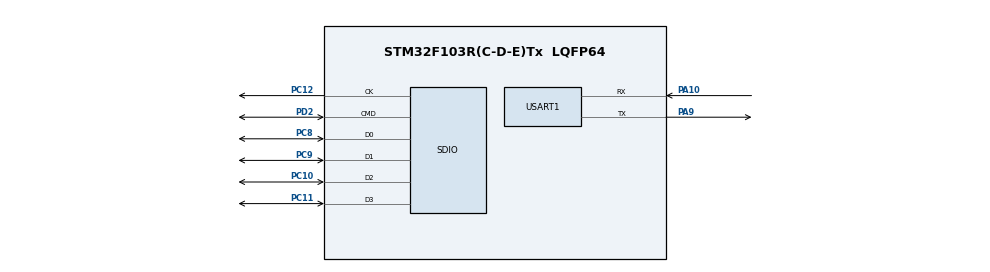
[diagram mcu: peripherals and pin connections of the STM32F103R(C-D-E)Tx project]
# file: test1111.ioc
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Dma.Request0=USART1_RX
Dma.Request1=USART1_TX
Dma.USART1_RX.0.Direction=DMA_PERIPH_TO_MEMORY
Dma.USART1_RX.0.Instance=DMA1_Channel5
Dma.USART1_RX.0.MemDataAlignment=DMA_MDATAALIGN_BYTE
Dma.USART1_RX.0.MemInc=DMA_MINC_ENABLE
Dma.USART1_RX.0.Mode=DMA_NORMAL
Dma.USART1_RX.0.PeriphDataAlignment=DMA_PDATAALIGN_BYTE
Dma.USART1_RX.0.PeriphInc=DMA_PINC_DISABLE
Dma.USART1_RX.0.Priority=DMA_PRIORITY_LOW
Dma.USART1_TX.1.Direction=DMA_MEMORY_TO_PERIPH
Dma.USART1_TX.1.Instance=DMA1_Channel4
Dma.USART1_TX.1.MemDataAlignment=DMA_MDATAALIGN_HALFWORD
Dma.USART1_TX.1.MemInc=DMA_MINC_ENABLE
Dma.USART1_TX.1.Mode=DMA_NORMAL
Dma.USART1_TX.1.PeriphDataAlignment=DMA_PDATAALIGN_HALFWORD
Dma.USART1_TX.1.PeriphInc=DMA_PINC_DISABLE
Dma.USART1_TX.1.Priority=DMA_PRIORITY_LOW
FREERTOS.Tasks01=defaultTask,0,128,StartDefaultTask,Default,NULL
Mcu.Family=STM32F1
Mcu.Name=STM32F103R(C-D-E)Tx
Mcu.Package=LQFP64
NVIC.DMA1_Channel4_IRQn=true\:5\:0\:false\:false\:true\:true
NVIC.DMA1_Channel5_IRQn=true\:5\:0\:false\:false\:true\:true
NVIC.PriorityGroup=NVIC_PRIORITYGROUP_4
PA10.Mode=Asynchronous
PA10.Signal=USART1_RX
PA9.Mode=Asynchronous
PA9.Signal=USART1_TX
PC10.Mode=SD_4_bits_Wide_bus
PC10.Signal=SDIO_D2
PC11.Mode=SD_4_bits_Wide_bus
PC11.Signal=SDIO_D3
PC12.Mode=SD_4_bits_Wide_bus
PC12.Signal=SDIO_CK
PC8.Mode=SD_4_bits_Wide_bus
PC8.Signal=SDIO_D0
PC9.Mode=SD_4_bits_Wide_bus
PC9.Signal=SDIO_D1
PD0-OSC_IN.Mode=HSE-External-Oscillator
PD0-OSC_IN.Signal=RCC_OSC_IN
PD1-OSC_OUT.Mode=HSE-External-Oscillator
PD1-OSC_OUT.Signal=RCC_OSC_OUT
PD2.Mode=SD_4_bits_Wide_bus
PD2.Signal=SDIO_CMD
ProjectManager.HeapSize=0x200
ProjectManager.StackSize=0x400
ProjectManager.TargetToolchain=MDK-ARM V5
RCC.AHBFreq_Value=72000000
RCC.APB1CLKDivider=RCC_HCLK_DIV2
RCC.APB1Freq_Value=36000000
RCC.APB1TimFreq_Value=72000000
RCC.APB2Freq_Value=72000000
RCC.APB2TimFreq_Value=72000000
RCC.HCLKFreq_Value=72000000
RCC.PLLMUL=RCC_PLL_MUL9
RCC.PLLSourceVirtual=RCC_PLLSOURCE_HSE
RCC.SYSCLKFreq_VALUE=72000000
RCC.SYSCLKSource=RCC_SYSCLKSOURCE_PLLCLK
RCC.USBFreq_Value=72000000
USART1.VirtualMode=VM_ASYNC
VP_FREERTOS_VS_ENABLE.Mode=Enabled
VP_SYS_VS_ND.Mode=No_Debug
VP_TIM3_VS_ClockSourceINT.Mode=Internal
board=test1111

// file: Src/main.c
/**
  ******************************************************************************
  * File Name          : main.c
  * Description        : Main program body
  ******************************************************************************
  * This notice applies to any and all portions of this file
  * that are not between comment pairs USER CODE BEGIN and
  * USER CODE END. Other portions of this file, whether
  * inserted by the user or by software development tools
  * are owned by their respective copyright owners.
  *
  * Copyright (c) 2017 STMicroelectronics International N.V.
  * All rights reserved.
  *
  * Redistribution and use in source and binary forms, with or without
  * modification, are permitted, provided that the following conditions are met:
  *
  * 1. Redistribution of source code must retain the above copyright notice,
  *    this list of conditions and the following disclaimer.
  * 2. Redistributions in binary form must reproduce the above copyright notice,
  *    this list of conditions and the following disclaimer in the documentation
  *    and/or other materials provided with the distribution.
  * 3. Neither the name of STMicroelectronics nor the names of other
  *    contributors to this software may be used to endorse or promote products
  *    derived from this software without specific written permission.
  * 4. This software, including modifications and/or derivative works of this
  *    software, must execute solely and exclusively on microcontroller or
  *    microprocessor devices manufactured by or for STMicroelectronics.
  * 5. Redistribution and use of this software other than as permitted under
  *    this license is void and will automatically terminate your rights under
  *    this license.
  *
  * THIS SOFTWARE IS PROVIDED BY STMICROELECTRONICS AND CONTRIBUTORS "AS IS"
  * AND ANY EXPRESS, IMPLIED OR STATUTORY WARRANTIES, INCLUDING, BUT NOT
  * LIMITED TO, THE IMPLIED WARRANTIES OF MERCHANTABILITY, FITNESS FOR A
  * PARTICULAR PURPOSE AND NON-INFRINGEMENT OF THIRD PARTY INTELLECTUAL PROPERTY
  * RIGHTS ARE DISCLAIMED TO THE FULLEST EXTENT PERMITTED BY LAW. IN NO EVENT
  * SHALL STMICROELECTRONICS OR CONTRIBUTORS BE LIABLE FOR ANY DIRECT, INDIRECT,
  * INCIDENTAL, SPECIAL, EXEMPLARY, OR CONSEQUENTIAL DAMAGES (INCLUDING, BUT NOT
  * LIMITED TO, PROCUREMENT OF SUBSTITUTE GOODS OR SERVICES; LOSS OF USE, DATA,
  * OR PROFITS; OR BUSINESS INTERRUPTION) HOWEVER CAUSED AND ON ANY THEORY OF
  * LIABILITY, WHETHER IN CONTRACT, STRICT LIABILITY, OR TORT (INCLUDING
  * NEGLIGENCE OR OTHERWISE) ARISING IN ANY WAY OUT OF THE USE OF THIS SOFTWARE,
  * EVEN IF ADVISED OF THE POSSIBILITY OF SUCH DAMAGE.
  *
  ******************************************************************************
  */
#include "main.h"
#include "stm32f1xx_hal.h"
#include "cmsis_os.h"
#include "dma.h"
#include "sdio.h"
#include "tim.h"
#include "usart.h"
#include "gpio.h"

/* USER CODE BEGIN PV */
/* Private variables ---------------------------------------------------------*/

/* USER CODE END PV */

void SystemClock_Config(void);
void MX_FREERTOS_Init(void);

/* USER CODE BEGIN PFP */
/* Private function prototypes -----------------------------------------------*/

/* USER CODE END PFP */

int main(void)
{

  /* MCU Configuration----------------------------------------------------------*/

  /* Reset of all peripherals, Initializes the Flash interface and the Systick. */
  HAL_Init();

  /* Configure the system clock */
  SystemClock_Config();

  /* Initialize all configured peripherals */
  MX_GPIO_Init();
  MX_DMA_Init();
  MX_USART1_UART_Init();
  MX_SDIO_SD_Init();
  MX_TIM3_Init();

  /* Call init function for freertos objects (in freertos.c) */
  MX_FREERTOS_Init();

  /* Start scheduler */
  osKernelStart();

  /* We should never get here as control is now taken by the scheduler */

  /* Infinite loop */
  while (1)
  {

  }

}

/** System Clock Configuration
*/
void SystemClock_Config(void)
{

  RCC_OscInitTypeDef RCC_OscInitStruct;
  RCC_ClkInitTypeDef RCC_ClkInitStruct;

    /**Initializes the CPU, AHB and APB busses clocks
    */
  RCC_OscInitStruct.OscillatorType = RCC_OSCILLATORTYPE_HSI;
  RCC_OscInitStruct.HSIState = RCC_HSI_ON;
  RCC_OscInitStruct.HSICalibrationValue = 16;
  RCC_OscInitStruct.PLL.PLLState = RCC_PLL_ON;
  RCC_OscInitStruct.PLL.PLLSource = RCC_PLLSOURCE_HSI_DIV2;
  RCC_OscInitStruct.PLL.PLLMUL = RCC_PLL_MUL16;
  if (HAL_RCC_OscConfig(&RCC_OscInitStruct) != HAL_OK)
  {
    _Error_Handler(__FILE__, __LINE__);
  }

    /**Initializes the CPU, AHB and APB busses clocks
    */
  RCC_ClkInitStruct.ClockType = RCC_CLOCKTYPE_HCLK|RCC_CLOCKTYPE_SYSCLK
                              |RCC_CLOCKTYPE_PCLK1|RCC_CLOCKTYPE_PCLK2;
  RCC_ClkInitStruct.SYSCLKSource = RCC_SYSCLKSOURCE_PLLCLK;
  RCC_ClkInitStruct.AHBCLKDivider = RCC_SYSCLK_DIV1;
  RCC_ClkInitStruct.APB1CLKDivider = RCC_HCLK_DIV2;
  RCC_ClkInitStruct.APB2CLKDivider = RCC_HCLK_DIV1;

  if (HAL_RCC_ClockConfig(&RCC_ClkInitStruct, FLASH_LATENCY_2) != HAL_OK)
  {
    _Error_Handler(__FILE__, __LINE__);
  }

    /**Configure the Systick interrupt time
    */
  HAL_SYSTICK_Config(HAL_RCC_GetHCLKFreq()/1000);

    /**Configure the Systick
    */
  HAL_SYSTICK_CLKSourceConfig(SYSTICK_CLKSOURCE_HCLK);

  /* SysTick_IRQn interrupt configuration */
  HAL_NVIC_SetPriority(SysTick_IRQn, 15, 0);
}

void _Error_Handler(char * file, int line)
{
  while(1)
  {
  }
}

/************************ (C) COPYRIGHT STMicroelectronics *****END OF FILE****/
